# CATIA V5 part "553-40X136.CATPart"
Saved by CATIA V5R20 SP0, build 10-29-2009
Part number: 553-40X136
Definition: NONE
Nomenclature: 553-40X136
Source: Unknown
Description: 553-40X136
Bounding box of the stored display mesh (mm): x 0 to 136, y -29.5 to 29.5, z -29.5 to 29.5
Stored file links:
  C:\Users\Utente\Desktop\IO LAVORO\3D X SITO CF\X SITO\PLASTICA\553\553-40X136.CATPart

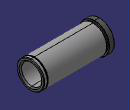
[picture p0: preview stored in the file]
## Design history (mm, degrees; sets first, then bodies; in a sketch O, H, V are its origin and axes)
Body1 "553-40X136" (main body)
  Solid1: solid without history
